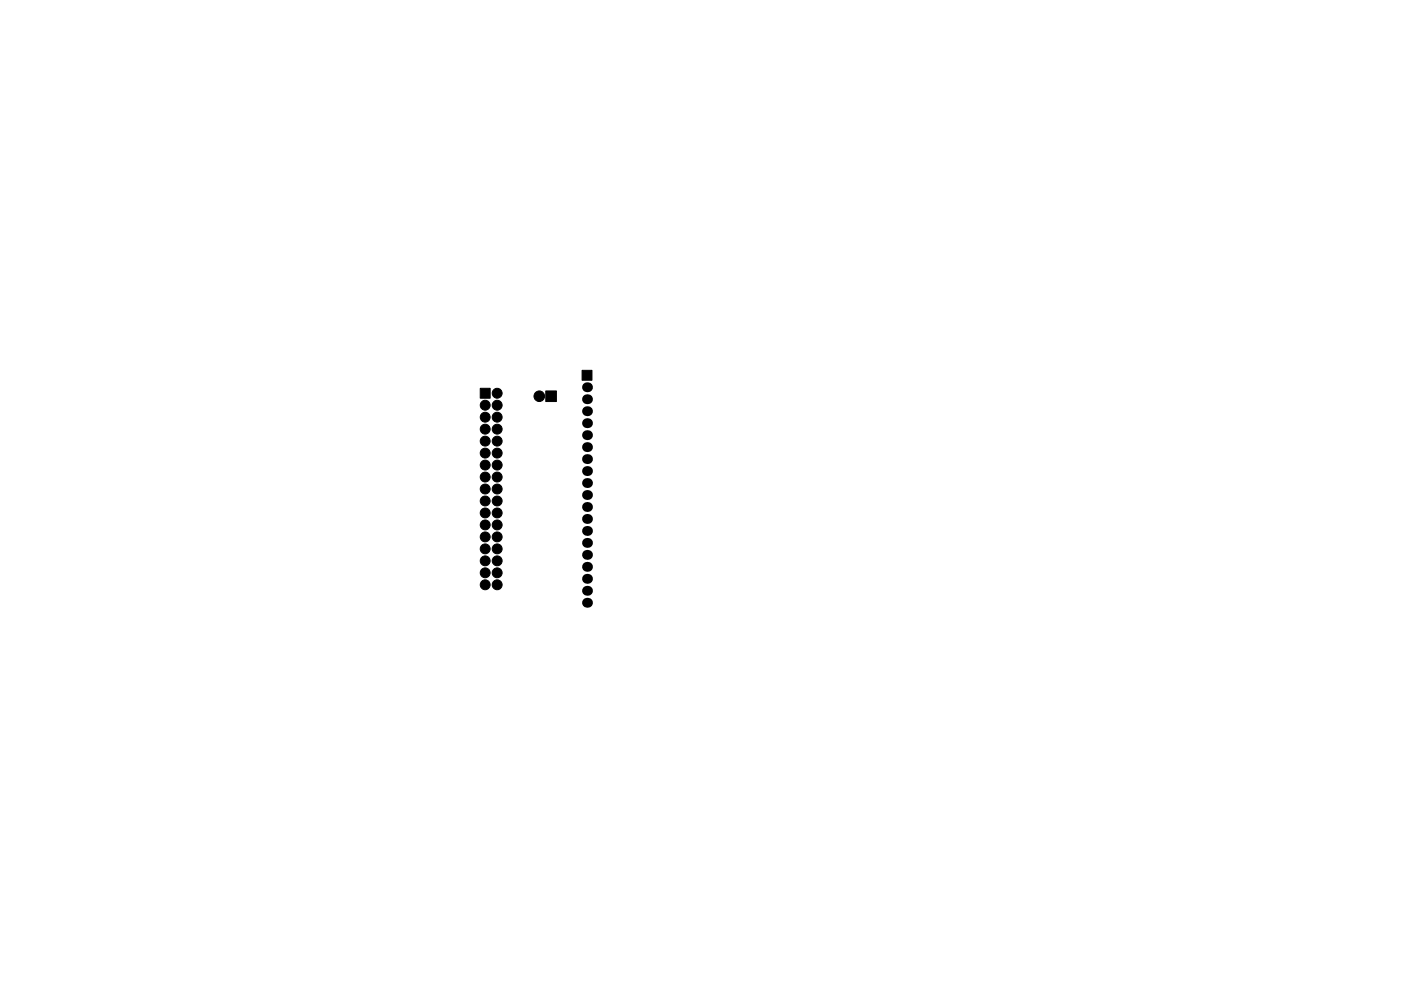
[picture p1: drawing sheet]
<svg xmlns="http://www.w3.org/2000/svg" width="297mm" height="210mm" viewBox="0 0 297 210" stroke-linecap="round" stroke-linejoin="round" font-family="sans-serif">
<g fill="#000" stroke="#000" stroke-width=".21">
<path d="M101.8 82.4h2.1v2.1h-2.1zM115.7 82.9h2.3v2.3h-2.3zM123.4 78.6h2.1v2.1h-2.1z"/>
<circle cx="102.9" cy="91.1" r="1.05"/>
<circle cx="102.9" cy="96.1" r="1.05"/>
<circle cx="102.9" cy="86" r="1.05"/>
<circle cx="102.9" cy="98.7" r="1.05"/>
<circle cx="102.9" cy="93.6" r="1.05"/>
<circle cx="102.9" cy="88.5" r="1.05"/>
<circle cx="105.4" cy="83.4" r="1.05"/>
<circle cx="105.4" cy="98.7" r="1.05"/>
<circle cx="105.4" cy="91.1" r="1.05"/>
<circle cx="105.4" cy="88.5" r="1.05"/>
<circle cx="105.4" cy="93.6" r="1.05"/>
<circle cx="105.4" cy="96.1" r="1.05"/>
<circle cx="105.4" cy="86" r="1.05"/>
<circle cx="114.3" cy="84.1" r="1.12"/>
<circle cx="102.9" cy="101.2" r="1.05"/>
<circle cx="102.9" cy="119" r="1.05"/>
<circle cx="102.9" cy="113.9" r="1.05"/>
<circle cx="102.9" cy="116.5" r="1.05"/>
<circle cx="102.9" cy="106.3" r="1.05"/>
<circle cx="102.9" cy="111.4" r="1.05"/>
<circle cx="102.9" cy="103.8" r="1.05"/>
<circle cx="102.9" cy="108.8" r="1.05"/>
<circle cx="105.4" cy="103.8" r="1.05"/>
<circle cx="105.4" cy="106.3" r="1.05"/>
<circle cx="105.4" cy="119" r="1.05"/>
<circle cx="105.4" cy="101.2" r="1.05"/>
<circle cx="105.4" cy="111.4" r="1.05"/>
<circle cx="105.4" cy="116.5" r="1.05"/>
<circle cx="105.4" cy="108.8" r="1.05"/>
<circle cx="105.4" cy="113.9" r="1.05"/>
<circle cx="102.9" cy="121.5" r="1.05"/>
<circle cx="102.9" cy="124.1" r="1.05"/>
<circle cx="105.4" cy="124.1" r="1.05"/>
<circle cx="105.4" cy="121.5" r="1.05"/>
</g>
<g fill="#000">
<circle cx="124.5" cy="89.8" r="1.05"/>
<circle cx="124.5" cy="84.7" r="1.05"/>
<circle cx="124.5" cy="87.2" r="1.05"/>
<circle cx="124.5" cy="97.4" r="1.05"/>
<circle cx="124.5" cy="99.9" r="1.05"/>
<circle cx="124.5" cy="82.2" r="1.05"/>
<circle cx="124.5" cy="92.3" r="1.05"/>
<circle cx="124.5" cy="94.9" r="1.05"/>
<circle cx="124.5" cy="102.5" r="1.05"/>
<circle cx="124.5" cy="107.6" r="1.05"/>
<circle cx="124.5" cy="110.1" r="1.05"/>
<circle cx="124.5" cy="112.6" r="1.05"/>
<circle cx="124.5" cy="105" r="1.05"/>
<circle cx="124.5" cy="115.2" r="1.05"/>
<circle cx="124.5" cy="117.7" r="1.05"/>
<circle cx="124.5" cy="125.3" r="1.05"/>
<circle cx="124.5" cy="120.3" r="1.05"/>
<circle cx="124.5" cy="122.8" r="1.05"/>
<circle cx="124.5" cy="127.9" r="1.05"/>
</g>
</svg>
